VERSION 5.7 ;
BUSBITCHARS "[]" ;
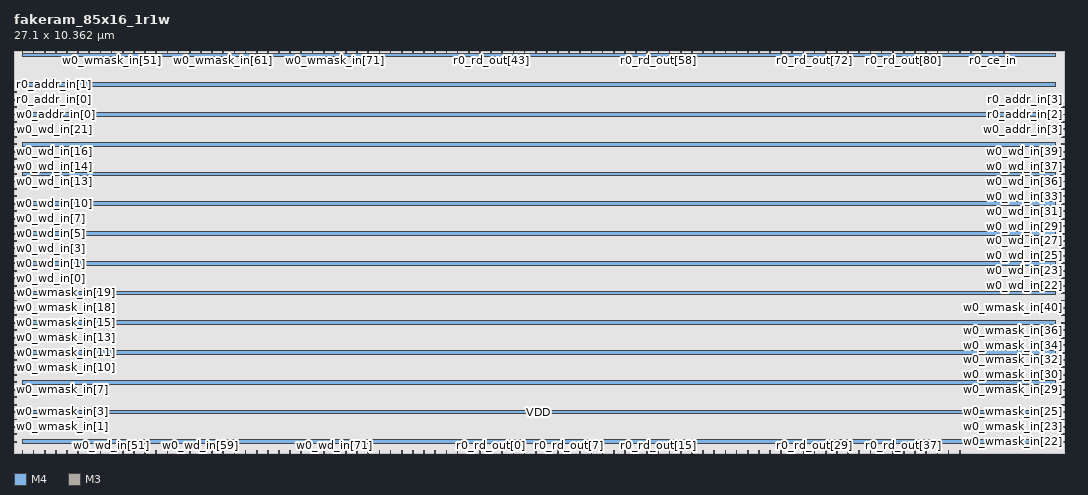
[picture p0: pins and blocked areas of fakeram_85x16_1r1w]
MACRO fakeram_85x16_1r1w
  FOREIGN fakeram_85x16_1r1w 0 0 ;
  SYMMETRY X Y R90 ;
  SIZE 27.100 BY 10.362 ;
  CLASS BLOCK ;
  PIN w0_wmask_in[0]
    DIRECTION INPUT ;
    USE SIGNAL ;
    SHAPE ABUTMENT ;
    PORT
      LAYER M4 ;
      RECT 0.000 0.276 0.072 0.300 ;
    END
  END w0_wmask_in[0]
  PIN w0_wmask_in[1]
    DIRECTION INPUT ;
    USE SIGNAL ;
    SHAPE ABUTMENT ;
    PORT
      LAYER M4 ;
      RECT 0.000 0.468 0.072 0.492 ;
    END
  END w0_wmask_in[1]
  PIN w0_wmask_in[2]
    DIRECTION INPUT ;
    USE SIGNAL ;
    SHAPE ABUTMENT ;
    PORT
      LAYER M4 ;
      RECT 0.000 0.660 0.072 0.684 ;
    END
  END w0_wmask_in[2]
  PIN w0_wmask_in[3]
    DIRECTION INPUT ;
    USE SIGNAL ;
    SHAPE ABUTMENT ;
    PORT
      LAYER M4 ;
      RECT 0.000 0.852 0.072 0.876 ;
    END
  END w0_wmask_in[3]
  PIN w0_wmask_in[4]
    DIRECTION INPUT ;
    USE SIGNAL ;
    SHAPE ABUTMENT ;
    PORT
      LAYER M4 ;
      RECT 0.000 1.044 0.072 1.068 ;
    END
  END w0_wmask_in[4]
  PIN w0_wmask_in[5]
    DIRECTION INPUT ;
    USE SIGNAL ;
    SHAPE ABUTMENT ;
    PORT
      LAYER M4 ;
      RECT 0.000 1.236 0.072 1.260 ;
    END
  END w0_wmask_in[5]
  PIN w0_wmask_in[6]
    DIRECTION INPUT ;
    USE SIGNAL ;
    SHAPE ABUTMENT ;
    PORT
      LAYER M4 ;
      RECT 0.000 1.428 0.072 1.452 ;
    END
  END w0_wmask_in[6]
  PIN w0_wmask_in[7]
    DIRECTION INPUT ;
    USE SIGNAL ;
    SHAPE ABUTMENT ;
    PORT
      LAYER M4 ;
      RECT 0.000 1.620 0.072 1.644 ;
    END
  END w0_wmask_in[7]
  PIN w0_wmask_in[8]
    DIRECTION INPUT ;
    USE SIGNAL ;
    SHAPE ABUTMENT ;
    PORT
      LAYER M4 ;
      RECT 0.000 1.812 0.072 1.836 ;
    END
  END w0_wmask_in[8]
  PIN w0_wmask_in[9]
    DIRECTION INPUT ;
    USE SIGNAL ;
    SHAPE ABUTMENT ;
    PORT
      LAYER M4 ;
      RECT 0.000 2.004 0.072 2.028 ;
    END
  END w0_wmask_in[9]
  PIN w0_wmask_in[10]
    DIRECTION INPUT ;
    USE SIGNAL ;
    SHAPE ABUTMENT ;
    PORT
      LAYER M4 ;
      RECT 0.000 2.196 0.072 2.220 ;
    END
  END w0_wmask_in[10]
  PIN w0_wmask_in[11]
    DIRECTION INPUT ;
    USE SIGNAL ;
    SHAPE ABUTMENT ;
    PORT
      LAYER M4 ;
      RECT 0.000 2.388 0.072 2.412 ;
    END
  END w0_wmask_in[11]
  PIN w0_wmask_in[12]
    DIRECTION INPUT ;
    USE SIGNAL ;
    SHAPE ABUTMENT ;
    PORT
      LAYER M4 ;
      RECT 0.000 2.580 0.072 2.604 ;
    END
  END w0_wmask_in[12]
  PIN w0_wmask_in[13]
    DIRECTION INPUT ;
    USE SIGNAL ;
    SHAPE ABUTMENT ;
    PORT
      LAYER M4 ;
      RECT 0.000 2.772 0.072 2.796 ;
    END
  END w0_wmask_in[13]
  PIN w0_wmask_in[14]
    DIRECTION INPUT ;
    USE SIGNAL ;
    SHAPE ABUTMENT ;
    PORT
      LAYER M4 ;
      RECT 0.000 2.964 0.072 2.988 ;
    END
  END w0_wmask_in[14]
  PIN w0_wmask_in[15]
    DIRECTION INPUT ;
    USE SIGNAL ;
    SHAPE ABUTMENT ;
    PORT
      LAYER M4 ;
      RECT 0.000 3.156 0.072 3.180 ;
    END
  END w0_wmask_in[15]
  PIN w0_wmask_in[16]
    DIRECTION INPUT ;
    USE SIGNAL ;
    SHAPE ABUTMENT ;
    PORT
      LAYER M4 ;
      RECT 0.000 3.348 0.072 3.372 ;
    END
  END w0_wmask_in[16]
  PIN w0_wmask_in[17]
    DIRECTION INPUT ;
    USE SIGNAL ;
    SHAPE ABUTMENT ;
    PORT
      LAYER M4 ;
      RECT 0.000 3.540 0.072 3.564 ;
    END
  END w0_wmask_in[17]
  PIN w0_wmask_in[18]
    DIRECTION INPUT ;
    USE SIGNAL ;
    SHAPE ABUTMENT ;
    PORT
      LAYER M4 ;
      RECT 0.000 3.732 0.072 3.756 ;
    END
  END w0_wmask_in[18]
  PIN w0_wmask_in[19]
    DIRECTION INPUT ;
    USE SIGNAL ;
    SHAPE ABUTMENT ;
    PORT
      LAYER M4 ;
      RECT 0.000 3.924 0.072 3.948 ;
    END
  END w0_wmask_in[19]
  PIN w0_wmask_in[20]
    DIRECTION INPUT ;
    USE SIGNAL ;
    SHAPE ABUTMENT ;
    PORT
      LAYER M4 ;
      RECT 0.000 4.116 0.072 4.140 ;
    END
  END w0_wmask_in[20]
  PIN w0_wmask_in[21]
    DIRECTION INPUT ;
    USE SIGNAL ;
    SHAPE ABUTMENT ;
    PORT
      LAYER M4 ;
      RECT 0.000 4.308 0.072 4.332 ;
    END
  END w0_wmask_in[21]
  PIN w0_wmask_in[22]
    DIRECTION INPUT ;
    USE SIGNAL ;
    SHAPE ABUTMENT ;
    PORT
      LAYER M4 ;
      RECT 27.028 0.276 27.100 0.300 ;
    END
  END w0_wmask_in[22]
  PIN w0_wmask_in[23]
    DIRECTION INPUT ;
    USE SIGNAL ;
    SHAPE ABUTMENT ;
    PORT
      LAYER M4 ;
      RECT 27.028 0.468 27.100 0.492 ;
    END
  END w0_wmask_in[23]
  PIN w0_wmask_in[24]
    DIRECTION INPUT ;
    USE SIGNAL ;
    SHAPE ABUTMENT ;
    PORT
      LAYER M4 ;
      RECT 27.028 0.660 27.100 0.684 ;
    END
  END w0_wmask_in[24]
  PIN w0_wmask_in[25]
    DIRECTION INPUT ;
    USE SIGNAL ;
    SHAPE ABUTMENT ;
    PORT
      LAYER M4 ;
      RECT 27.028 0.852 27.100 0.876 ;
    END
  END w0_wmask_in[25]
  PIN w0_wmask_in[26]
    DIRECTION INPUT ;
    USE SIGNAL ;
    SHAPE ABUTMENT ;
    PORT
      LAYER M4 ;
      RECT 27.028 1.044 27.100 1.068 ;
    END
  END w0_wmask_in[26]
  PIN w0_wmask_in[27]
    DIRECTION INPUT ;
    USE SIGNAL ;
    SHAPE ABUTMENT ;
    PORT
      LAYER M4 ;
      RECT 27.028 1.236 27.100 1.260 ;
    END
  END w0_wmask_in[27]
  PIN w0_wmask_in[28]
    DIRECTION INPUT ;
    USE SIGNAL ;
    SHAPE ABUTMENT ;
    PORT
      LAYER M4 ;
      RECT 27.028 1.428 27.100 1.452 ;
    END
  END w0_wmask_in[28]
  PIN w0_wmask_in[29]
    DIRECTION INPUT ;
    USE SIGNAL ;
    SHAPE ABUTMENT ;
    PORT
      LAYER M4 ;
      RECT 27.028 1.620 27.100 1.644 ;
    END
  END w0_wmask_in[29]
  PIN w0_wmask_in[30]
    DIRECTION INPUT ;
    USE SIGNAL ;
    SHAPE ABUTMENT ;
    PORT
      LAYER M4 ;
      RECT 27.028 1.812 27.100 1.836 ;
    END
  END w0_wmask_in[30]
  PIN w0_wmask_in[31]
    DIRECTION INPUT ;
    USE SIGNAL ;
    SHAPE ABUTMENT ;
    PORT
      LAYER M4 ;
      RECT 27.028 2.004 27.100 2.028 ;
    END
  END w0_wmask_in[31]
  PIN w0_wmask_in[32]
    DIRECTION INPUT ;
    USE SIGNAL ;
    SHAPE ABUTMENT ;
    PORT
      LAYER M4 ;
      RECT 27.028 2.196 27.100 2.220 ;
    END
  END w0_wmask_in[32]
  PIN w0_wmask_in[33]
    DIRECTION INPUT ;
    USE SIGNAL ;
    SHAPE ABUTMENT ;
    PORT
      LAYER M4 ;
      RECT 27.028 2.388 27.100 2.412 ;
    END
  END w0_wmask_in[33]
  PIN w0_wmask_in[34]
    DIRECTION INPUT ;
    USE SIGNAL ;
    SHAPE ABUTMENT ;
    PORT
      LAYER M4 ;
      RECT 27.028 2.580 27.100 2.604 ;
    END
  END w0_wmask_in[34]
  PIN w0_wmask_in[35]
    DIRECTION INPUT ;
    USE SIGNAL ;
    SHAPE ABUTMENT ;
    PORT
      LAYER M4 ;
      RECT 27.028 2.772 27.100 2.796 ;
    END
  END w0_wmask_in[35]
  PIN w0_wmask_in[36]
    DIRECTION INPUT ;
    USE SIGNAL ;
    SHAPE ABUTMENT ;
    PORT
      LAYER M4 ;
      RECT 27.028 2.964 27.100 2.988 ;
    END
  END w0_wmask_in[36]
  PIN w0_wmask_in[37]
    DIRECTION INPUT ;
    USE SIGNAL ;
    SHAPE ABUTMENT ;
    PORT
      LAYER M4 ;
      RECT 27.028 3.156 27.100 3.180 ;
    END
  END w0_wmask_in[37]
  PIN w0_wmask_in[38]
    DIRECTION INPUT ;
    USE SIGNAL ;
    SHAPE ABUTMENT ;
    PORT
      LAYER M4 ;
      RECT 27.028 3.348 27.100 3.372 ;
    END
  END w0_wmask_in[38]
  PIN w0_wmask_in[39]
    DIRECTION INPUT ;
    USE SIGNAL ;
    SHAPE ABUTMENT ;
    PORT
      LAYER M4 ;
      RECT 27.028 3.540 27.100 3.564 ;
    END
  END w0_wmask_in[39]
  PIN w0_wmask_in[40]
    DIRECTION INPUT ;
    USE SIGNAL ;
    SHAPE ABUTMENT ;
    PORT
      LAYER M4 ;
      RECT 27.028 3.732 27.100 3.756 ;
    END
  END w0_wmask_in[40]
  PIN w0_wmask_in[41]
    DIRECTION INPUT ;
    USE SIGNAL ;
    SHAPE ABUTMENT ;
    PORT
      LAYER M4 ;
      RECT 27.028 3.924 27.100 3.948 ;
    END
  END w0_wmask_in[41]
  PIN w0_wmask_in[42]
    DIRECTION INPUT ;
    USE SIGNAL ;
    SHAPE ABUTMENT ;
    PORT
      LAYER M4 ;
      RECT 27.028 4.116 27.100 4.140 ;
    END
  END w0_wmask_in[42]
  PIN w0_wmask_in[43]
    DIRECTION INPUT ;
    USE SIGNAL ;
    SHAPE ABUTMENT ;
    PORT
      LAYER M3 ;
      RECT 0.207 10.308 0.225 10.362 ;
    END
  END w0_wmask_in[43]
  PIN w0_wmask_in[44]
    DIRECTION INPUT ;
    USE SIGNAL ;
    SHAPE ABUTMENT ;
    PORT
      LAYER M3 ;
      RECT 0.495 10.308 0.513 10.362 ;
    END
  END w0_wmask_in[44]
  PIN w0_wmask_in[45]
    DIRECTION INPUT ;
    USE SIGNAL ;
    SHAPE ABUTMENT ;
    PORT
      LAYER M3 ;
      RECT 0.783 10.308 0.801 10.362 ;
    END
  END w0_wmask_in[45]
  PIN w0_wmask_in[46]
    DIRECTION INPUT ;
    USE SIGNAL ;
    SHAPE ABUTMENT ;
    PORT
      LAYER M3 ;
      RECT 1.071 10.308 1.089 10.362 ;
    END
  END w0_wmask_in[46]
  PIN w0_wmask_in[47]
    DIRECTION INPUT ;
    USE SIGNAL ;
    SHAPE ABUTMENT ;
    PORT
      LAYER M3 ;
      RECT 1.359 10.308 1.377 10.362 ;
    END
  END w0_wmask_in[47]
  PIN w0_wmask_in[48]
    DIRECTION INPUT ;
    USE SIGNAL ;
    SHAPE ABUTMENT ;
    PORT
      LAYER M3 ;
      RECT 1.647 10.308 1.665 10.362 ;
    END
  END w0_wmask_in[48]
  PIN w0_wmask_in[49]
    DIRECTION INPUT ;
    USE SIGNAL ;
    SHAPE ABUTMENT ;
    PORT
      LAYER M3 ;
      RECT 1.935 10.308 1.953 10.362 ;
    END
  END w0_wmask_in[49]
  PIN w0_wmask_in[50]
    DIRECTION INPUT ;
    USE SIGNAL ;
    SHAPE ABUTMENT ;
    PORT
      LAYER M3 ;
      RECT 2.223 10.308 2.241 10.362 ;
    END
  END w0_wmask_in[50]
  PIN w0_wmask_in[51]
    DIRECTION INPUT ;
    USE SIGNAL ;
    SHAPE ABUTMENT ;
    PORT
      LAYER M3 ;
      RECT 2.511 10.308 2.529 10.362 ;
    END
  END w0_wmask_in[51]
  PIN w0_wmask_in[52]
    DIRECTION INPUT ;
    USE SIGNAL ;
    SHAPE ABUTMENT ;
    PORT
      LAYER M3 ;
      RECT 2.799 10.308 2.817 10.362 ;
    END
  END w0_wmask_in[52]
  PIN w0_wmask_in[53]
    DIRECTION INPUT ;
    USE SIGNAL ;
    SHAPE ABUTMENT ;
    PORT
      LAYER M3 ;
      RECT 3.087 10.308 3.105 10.362 ;
    END
  END w0_wmask_in[53]
  PIN w0_wmask_in[54]
    DIRECTION INPUT ;
    USE SIGNAL ;
    SHAPE ABUTMENT ;
    PORT
      LAYER M3 ;
      RECT 3.375 10.308 3.393 10.362 ;
    END
  END w0_wmask_in[54]
  PIN w0_wmask_in[55]
    DIRECTION INPUT ;
    USE SIGNAL ;
    SHAPE ABUTMENT ;
    PORT
      LAYER M3 ;
      RECT 3.663 10.308 3.681 10.362 ;
    END
  END w0_wmask_in[55]
  PIN w0_wmask_in[56]
    DIRECTION INPUT ;
    USE SIGNAL ;
    SHAPE ABUTMENT ;
    PORT
      LAYER M3 ;
      RECT 3.951 10.308 3.969 10.362 ;
    END
  END w0_wmask_in[56]
  PIN w0_wmask_in[57]
    DIRECTION INPUT ;
    USE SIGNAL ;
    SHAPE ABUTMENT ;
    PORT
      LAYER M3 ;
      RECT 4.239 10.308 4.257 10.362 ;
    END
  END w0_wmask_in[57]
  PIN w0_wmask_in[58]
    DIRECTION INPUT ;
    USE SIGNAL ;
    SHAPE ABUTMENT ;
    PORT
      LAYER M3 ;
      RECT 4.527 10.308 4.545 10.362 ;
    END
  END w0_wmask_in[58]
  PIN w0_wmask_in[59]
    DIRECTION INPUT ;
    USE SIGNAL ;
    SHAPE ABUTMENT ;
    PORT
      LAYER M3 ;
      RECT 4.815 10.308 4.833 10.362 ;
    END
  END w0_wmask_in[59]
  PIN w0_wmask_in[60]
    DIRECTION INPUT ;
    USE SIGNAL ;
    SHAPE ABUTMENT ;
    PORT
      LAYER M3 ;
      RECT 5.103 10.308 5.121 10.362 ;
    END
  END w0_wmask_in[60]
  PIN w0_wmask_in[61]
    DIRECTION INPUT ;
    USE SIGNAL ;
    SHAPE ABUTMENT ;
    PORT
      LAYER M3 ;
      RECT 5.391 10.308 5.409 10.362 ;
    END
  END w0_wmask_in[61]
  PIN w0_wmask_in[62]
    DIRECTION INPUT ;
    USE SIGNAL ;
    SHAPE ABUTMENT ;
    PORT
      LAYER M3 ;
      RECT 5.679 10.308 5.697 10.362 ;
    END
  END w0_wmask_in[62]
  PIN w0_wmask_in[63]
    DIRECTION INPUT ;
    USE SIGNAL ;
    SHAPE ABUTMENT ;
    PORT
      LAYER M3 ;
      RECT 5.967 10.308 5.985 10.362 ;
    END
  END w0_wmask_in[63]
  PIN w0_wmask_in[64]
    DIRECTION INPUT ;
    USE SIGNAL ;
    SHAPE ABUTMENT ;
    PORT
      LAYER M3 ;
      RECT 6.255 10.308 6.273 10.362 ;
    END
  END w0_wmask_in[64]
  PIN w0_wmask_in[65]
    DIRECTION INPUT ;
    USE SIGNAL ;
    SHAPE ABUTMENT ;
    PORT
      LAYER M3 ;
      RECT 6.543 10.308 6.561 10.362 ;
    END
  END w0_wmask_in[65]
  PIN w0_wmask_in[66]
    DIRECTION INPUT ;
    USE SIGNAL ;
    SHAPE ABUTMENT ;
    PORT
      LAYER M3 ;
      RECT 6.831 10.308 6.849 10.362 ;
    END
  END w0_wmask_in[66]
  PIN w0_wmask_in[67]
    DIRECTION INPUT ;
    USE SIGNAL ;
    SHAPE ABUTMENT ;
    PORT
      LAYER M3 ;
      RECT 7.119 10.308 7.137 10.362 ;
    END
  END w0_wmask_in[67]
  PIN w0_wmask_in[68]
    DIRECTION INPUT ;
    USE SIGNAL ;
    SHAPE ABUTMENT ;
    PORT
      LAYER M3 ;
      RECT 7.407 10.308 7.425 10.362 ;
    END
  END w0_wmask_in[68]
  PIN w0_wmask_in[69]
    DIRECTION INPUT ;
    USE SIGNAL ;
    SHAPE ABUTMENT ;
    PORT
      LAYER M3 ;
      RECT 7.695 10.308 7.713 10.362 ;
    END
  END w0_wmask_in[69]
  PIN w0_wmask_in[70]
    DIRECTION INPUT ;
    USE SIGNAL ;
    SHAPE ABUTMENT ;
    PORT
      LAYER M3 ;
      RECT 7.983 10.308 8.001 10.362 ;
    END
  END w0_wmask_in[70]
  PIN w0_wmask_in[71]
    DIRECTION INPUT ;
    USE SIGNAL ;
    SHAPE ABUTMENT ;
    PORT
      LAYER M3 ;
      RECT 8.271 10.308 8.289 10.362 ;
    END
  END w0_wmask_in[71]
  PIN w0_wmask_in[72]
    DIRECTION INPUT ;
    USE SIGNAL ;
    SHAPE ABUTMENT ;
    PORT
      LAYER M3 ;
      RECT 8.559 10.308 8.577 10.362 ;
    END
  END w0_wmask_in[72]
  PIN w0_wmask_in[73]
    DIRECTION INPUT ;
    USE SIGNAL ;
    SHAPE ABUTMENT ;
    PORT
      LAYER M3 ;
      RECT 8.847 10.308 8.865 10.362 ;
    END
  END w0_wmask_in[73]
  PIN w0_wmask_in[74]
    DIRECTION INPUT ;
    USE SIGNAL ;
    SHAPE ABUTMENT ;
    PORT
      LAYER M3 ;
      RECT 9.135 10.308 9.153 10.362 ;
    END
  END w0_wmask_in[74]
  PIN w0_wmask_in[75]
    DIRECTION INPUT ;
    USE SIGNAL ;
    SHAPE ABUTMENT ;
    PORT
      LAYER M3 ;
      RECT 9.423 10.308 9.441 10.362 ;
    END
  END w0_wmask_in[75]
  PIN w0_wmask_in[76]
    DIRECTION INPUT ;
    USE SIGNAL ;
    SHAPE ABUTMENT ;
    PORT
      LAYER M3 ;
      RECT 9.711 10.308 9.729 10.362 ;
    END
  END w0_wmask_in[76]
  PIN w0_wmask_in[77]
    DIRECTION INPUT ;
    USE SIGNAL ;
    SHAPE ABUTMENT ;
    PORT
      LAYER M3 ;
      RECT 9.999 10.308 10.017 10.362 ;
    END
  END w0_wmask_in[77]
  PIN w0_wmask_in[78]
    DIRECTION INPUT ;
    USE SIGNAL ;
    SHAPE ABUTMENT ;
    PORT
      LAYER M3 ;
      RECT 10.287 10.308 10.305 10.362 ;
    END
  END w0_wmask_in[78]
  PIN w0_wmask_in[79]
    DIRECTION INPUT ;
    USE SIGNAL ;
    SHAPE ABUTMENT ;
    PORT
      LAYER M3 ;
      RECT 10.575 10.308 10.593 10.362 ;
    END
  END w0_wmask_in[79]
  PIN w0_wmask_in[80]
    DIRECTION INPUT ;
    USE SIGNAL ;
    SHAPE ABUTMENT ;
    PORT
      LAYER M3 ;
      RECT 10.863 10.308 10.881 10.362 ;
    END
  END w0_wmask_in[80]
  PIN w0_wmask_in[81]
    DIRECTION INPUT ;
    USE SIGNAL ;
    SHAPE ABUTMENT ;
    PORT
      LAYER M3 ;
      RECT 11.151 10.308 11.169 10.362 ;
    END
  END w0_wmask_in[81]
  PIN w0_wmask_in[82]
    DIRECTION INPUT ;
    USE SIGNAL ;
    SHAPE ABUTMENT ;
    PORT
      LAYER M3 ;
      RECT 11.439 10.308 11.457 10.362 ;
    END
  END w0_wmask_in[82]
  PIN w0_wmask_in[83]
    DIRECTION INPUT ;
    USE SIGNAL ;
    SHAPE ABUTMENT ;
    PORT
      LAYER M3 ;
      RECT 11.727 10.308 11.745 10.362 ;
    END
  END w0_wmask_in[83]
  PIN w0_wmask_in[84]
    DIRECTION INPUT ;
    USE SIGNAL ;
    SHAPE ABUTMENT ;
    PORT
      LAYER M3 ;
      RECT 12.015 10.308 12.033 10.362 ;
    END
  END w0_wmask_in[84]
  PIN w0_wd_in[0]
    DIRECTION INPUT ;
    USE SIGNAL ;
    SHAPE ABUTMENT ;
    PORT
      LAYER M4 ;
      RECT 0.000 4.500 0.072 4.524 ;
    END
  END w0_wd_in[0]
  PIN w0_wd_in[1]
    DIRECTION INPUT ;
    USE SIGNAL ;
    SHAPE ABUTMENT ;
    PORT
      LAYER M4 ;
      RECT 0.000 4.692 0.072 4.716 ;
    END
  END w0_wd_in[1]
  PIN w0_wd_in[2]
    DIRECTION INPUT ;
    USE SIGNAL ;
    SHAPE ABUTMENT ;
    PORT
      LAYER M4 ;
      RECT 0.000 4.884 0.072 4.908 ;
    END
  END w0_wd_in[2]
  PIN w0_wd_in[3]
    DIRECTION INPUT ;
    USE SIGNAL ;
    SHAPE ABUTMENT ;
    PORT
      LAYER M4 ;
      RECT 0.000 5.076 0.072 5.100 ;
    END
  END w0_wd_in[3]
  PIN w0_wd_in[4]
    DIRECTION INPUT ;
    USE SIGNAL ;
    SHAPE ABUTMENT ;
    PORT
      LAYER M4 ;
      RECT 0.000 5.268 0.072 5.292 ;
    END
  END w0_wd_in[4]
  PIN w0_wd_in[5]
    DIRECTION INPUT ;
    USE SIGNAL ;
    SHAPE ABUTMENT ;
    PORT
      LAYER M4 ;
      RECT 0.000 5.460 0.072 5.484 ;
    END
  END w0_wd_in[5]
  PIN w0_wd_in[6]
    DIRECTION INPUT ;
    USE SIGNAL ;
    SHAPE ABUTMENT ;
    PORT
      LAYER M4 ;
      RECT 0.000 5.652 0.072 5.676 ;
    END
  END w0_wd_in[6]
  PIN w0_wd_in[7]
    DIRECTION INPUT ;
    USE SIGNAL ;
    SHAPE ABUTMENT ;
    PORT
      LAYER M4 ;
      RECT 0.000 5.844 0.072 5.868 ;
    END
  END w0_wd_in[7]
  PIN w0_wd_in[8]
    DIRECTION INPUT ;
    USE SIGNAL ;
    SHAPE ABUTMENT ;
    PORT
      LAYER M4 ;
      RECT 0.000 6.036 0.072 6.060 ;
    END
  END w0_wd_in[8]
  PIN w0_wd_in[9]
    DIRECTION INPUT ;
    USE SIGNAL ;
    SHAPE ABUTMENT ;
    PORT
      LAYER M4 ;
      RECT 0.000 6.228 0.072 6.252 ;
    END
  END w0_wd_in[9]
  PIN w0_wd_in[10]
    DIRECTION INPUT ;
    USE SIGNAL ;
    SHAPE ABUTMENT ;
    PORT
      LAYER M4 ;
      RECT 0.000 6.420 0.072 6.444 ;
    END
  END w0_wd_in[10]
  PIN w0_wd_in[11]
    DIRECTION INPUT ;
    USE SIGNAL ;
    SHAPE ABUTMENT ;
    PORT
      LAYER M4 ;
      RECT 0.000 6.612 0.072 6.636 ;
    END
  END w0_wd_in[11]
  PIN w0_wd_in[12]
    DIRECTION INPUT ;
    USE SIGNAL ;
    SHAPE ABUTMENT ;
    PORT
      LAYER M4 ;
      RECT 0.000 6.804 0.072 6.828 ;
    END
  END w0_wd_in[12]
  PIN w0_wd_in[13]
    DIRECTION INPUT ;
    USE SIGNAL ;
    SHAPE ABUTMENT ;
    PORT
      LAYER M4 ;
      RECT 0.000 6.996 0.072 7.020 ;
    END
  END w0_wd_in[13]
  PIN w0_wd_in[14]
    DIRECTION INPUT ;
    USE SIGNAL ;
    SHAPE ABUTMENT ;
    PORT
      LAYER M4 ;
      RECT 0.000 7.188 0.072 7.212 ;
    END
  END w0_wd_in[14]
  PIN w0_wd_in[15]
    DIRECTION INPUT ;
    USE SIGNAL ;
    SHAPE ABUTMENT ;
    PORT
      LAYER M4 ;
      RECT 0.000 7.380 0.072 7.404 ;
    END
  END w0_wd_in[15]
  PIN w0_wd_in[16]
    DIRECTION INPUT ;
    USE SIGNAL ;
    SHAPE ABUTMENT ;
    PORT
      LAYER M4 ;
      RECT 0.000 7.572 0.072 7.596 ;
    END
  END w0_wd_in[16]
  PIN w0_wd_in[17]
    DIRECTION INPUT ;
    USE SIGNAL ;
    SHAPE ABUTMENT ;
    PORT
      LAYER M4 ;
      RECT 0.000 7.764 0.072 7.788 ;
    END
  END w0_wd_in[17]
  PIN w0_wd_in[18]
    DIRECTION INPUT ;
    USE SIGNAL ;
    SHAPE ABUTMENT ;
    PORT
      LAYER M4 ;
      RECT 0.000 7.956 0.072 7.980 ;
    END
  END w0_wd_in[18]
  PIN w0_wd_in[19]
    DIRECTION INPUT ;
    USE SIGNAL ;
    SHAPE ABUTMENT ;
    PORT
      LAYER M4 ;
      RECT 0.000 8.148 0.072 8.172 ;
    END
  END w0_wd_in[19]
  PIN w0_wd_in[20]
    DIRECTION INPUT ;
    USE SIGNAL ;
    SHAPE ABUTMENT ;
    PORT
      LAYER M4 ;
      RECT 0.000 8.340 0.072 8.364 ;
    END
  END w0_wd_in[20]
  PIN w0_wd_in[21]
    DIRECTION INPUT ;
    USE SIGNAL ;
    SHAPE ABUTMENT ;
    PORT
      LAYER M4 ;
      RECT 0.000 8.532 0.072 8.556 ;
    END
  END w0_wd_in[21]
  PIN w0_wd_in[22]
    DIRECTION INPUT ;
    USE SIGNAL ;
    SHAPE ABUTMENT ;
    PORT
      LAYER M4 ;
      RECT 27.028 4.308 27.100 4.332 ;
    END
  END w0_wd_in[22]
  PIN w0_wd_in[23]
    DIRECTION INPUT ;
    USE SIGNAL ;
    SHAPE ABUTMENT ;
    PORT
      LAYER M4 ;
      RECT 27.028 4.500 27.100 4.524 ;
    END
  END w0_wd_in[23]
  PIN w0_wd_in[24]
    DIRECTION INPUT ;
    USE SIGNAL ;
    SHAPE ABUTMENT ;
    PORT
      LAYER M4 ;
      RECT 27.028 4.692 27.100 4.716 ;
    END
  END w0_wd_in[24]
  PIN w0_wd_in[25]
    DIRECTION INPUT ;
    USE SIGNAL ;
    SHAPE ABUTMENT ;
    PORT
      LAYER M4 ;
      RECT 27.028 4.884 27.100 4.908 ;
    END
  END w0_wd_in[25]
  PIN w0_wd_in[26]
    DIRECTION INPUT ;
    USE SIGNAL ;
    SHAPE ABUTMENT ;
    PORT
      LAYER M4 ;
      RECT 27.028 5.076 27.100 5.100 ;
    END
  END w0_wd_in[26]
  PIN w0_wd_in[27]
    DIRECTION INPUT ;
    USE SIGNAL ;
    SHAPE ABUTMENT ;
    PORT
      LAYER M4 ;
      RECT 27.028 5.268 27.100 5.292 ;
    END
  END w0_wd_in[27]
  PIN w0_wd_in[28]
    DIRECTION INPUT ;
    USE SIGNAL ;
    SHAPE ABUTMENT ;
    PORT
      LAYER M4 ;
      RECT 27.028 5.460 27.100 5.484 ;
    END
  END w0_wd_in[28]
  PIN w0_wd_in[29]
    DIRECTION INPUT ;
    USE SIGNAL ;
    SHAPE ABUTMENT ;
    PORT
      LAYER M4 ;
      RECT 27.028 5.652 27.100 5.676 ;
    END
  END w0_wd_in[29]
  PIN w0_wd_in[30]
    DIRECTION INPUT ;
    USE SIGNAL ;
    SHAPE ABUTMENT ;
    PORT
      LAYER M4 ;
      RECT 27.028 5.844 27.100 5.868 ;
    END
  END w0_wd_in[30]
  PIN w0_wd_in[31]
    DIRECTION INPUT ;
    USE SIGNAL ;
    SHAPE ABUTMENT ;
    PORT
      LAYER M4 ;
      RECT 27.028 6.036 27.100 6.060 ;
    END
  END w0_wd_in[31]
  PIN w0_wd_in[32]
    DIRECTION INPUT ;
    USE SIGNAL ;
    SHAPE ABUTMENT ;
    PORT
      LAYER M4 ;
      RECT 27.028 6.228 27.100 6.252 ;
    END
  END w0_wd_in[32]
  PIN w0_wd_in[33]
    DIRECTION INPUT ;
    USE SIGNAL ;
    SHAPE ABUTMENT ;
    PORT
      LAYER M4 ;
      RECT 27.028 6.420 27.100 6.444 ;
    END
  END w0_wd_in[33]
  PIN w0_wd_in[34]
    DIRECTION INPUT ;
    USE SIGNAL ;
    SHAPE ABUTMENT ;
    PORT
      LAYER M4 ;
      RECT 27.028 6.612 27.100 6.636 ;
    END
  END w0_wd_in[34]
  PIN w0_wd_in[35]
    DIRECTION INPUT ;
    USE SIGNAL ;
    SHAPE ABUTMENT ;
    PORT
      LAYER M4 ;
      RECT 27.028 6.804 27.100 6.828 ;
    END
  END w0_wd_in[35]
  PIN w0_wd_in[36]
    DIRECTION INPUT ;
    USE SIGNAL ;
    SHAPE ABUTMENT ;
    PORT
      LAYER M4 ;
      RECT 27.028 6.996 27.100 7.020 ;
    END
  END w0_wd_in[36]
  PIN w0_wd_in[37]
    DIRECTION INPUT ;
    USE SIGNAL ;
    SHAPE ABUTMENT ;
    PORT
      LAYER M4 ;
      RECT 27.028 7.188 27.100 7.212 ;
    END
  END w0_wd_in[37]
  PIN w0_wd_in[38]
    DIRECTION INPUT ;
    USE SIGNAL ;
    SHAPE ABUTMENT ;
    PORT
      LAYER M4 ;
      RECT 27.028 7.380 27.100 7.404 ;
    END
  END w0_wd_in[38]
  PIN w0_wd_in[39]
    DIRECTION INPUT ;
    USE SIGNAL ;
    SHAPE ABUTMENT ;
    PORT
      LAYER M4 ;
      RECT 27.028 7.572 27.100 7.596 ;
    END
  END w0_wd_in[39]
  PIN w0_wd_in[40]
    DIRECTION INPUT ;
    USE SIGNAL ;
    SHAPE ABUTMENT ;
    PORT
      LAYER M4 ;
      RECT 27.028 7.764 27.100 7.788 ;
    END
  END w0_wd_in[40]
  PIN w0_wd_in[41]
    DIRECTION INPUT ;
    USE SIGNAL ;
    SHAPE ABUTMENT ;
    PORT
      LAYER M4 ;
      RECT 27.028 7.956 27.100 7.980 ;
    END
  END w0_wd_in[41]
  PIN w0_wd_in[42]
    DIRECTION INPUT ;
    USE SIGNAL ;
    SHAPE ABUTMENT ;
    PORT
      LAYER M4 ;
      RECT 27.028 8.148 27.100 8.172 ;
    END
  END w0_wd_in[42]
  PIN w0_wd_in[43]
    DIRECTION OUTPUT ;
    USE SIGNAL ;
    SHAPE ABUTMENT ;
    PORT
      LAYER M3 ;
      RECT 0.207 0.000 0.225 0.054 ;
    END
  END w0_wd_in[43]
  PIN w0_wd_in[44]
    DIRECTION OUTPUT ;
    USE SIGNAL ;
    SHAPE ABUTMENT ;
    PORT
      LAYER M3 ;
      RECT 0.495 0.000 0.513 0.054 ;
    END
  END w0_wd_in[44]
  PIN w0_wd_in[45]
    DIRECTION OUTPUT ;
    USE SIGNAL ;
    SHAPE ABUTMENT ;
    PORT
      LAYER M3 ;
      RECT 0.783 0.000 0.801 0.054 ;
    END
  END w0_wd_in[45]
  PIN w0_wd_in[46]
    DIRECTION OUTPUT ;
    USE SIGNAL ;
    SHAPE ABUTMENT ;
    PORT
      LAYER M3 ;
      RECT 1.071 0.000 1.089 0.054 ;
    END
  END w0_wd_in[46]
  PIN w0_wd_in[47]
    DIRECTION OUTPUT ;
    USE SIGNAL ;
    SHAPE ABUTMENT ;
    PORT
      LAYER M3 ;
      RECT 1.359 0.000 1.377 0.054 ;
    END
  END w0_wd_in[47]
  PIN w0_wd_in[48]
    DIRECTION OUTPUT ;
    USE SIGNAL ;
    SHAPE ABUTMENT ;
    PORT
      LAYER M3 ;
      RECT 1.647 0.000 1.665 0.054 ;
    END
  END w0_wd_in[48]
  PIN w0_wd_in[49]
    DIRECTION OUTPUT ;
    USE SIGNAL ;
    SHAPE ABUTMENT ;
    PORT
      LAYER M3 ;
      RECT 1.935 0.000 1.953 0.054 ;
    END
  END w0_wd_in[49]
  PIN w0_wd_in[50]
    DIRECTION OUTPUT ;
    USE SIGNAL ;
    SHAPE ABUTMENT ;
    PORT
      LAYER M3 ;
      RECT 2.223 0.000 2.241 0.054 ;
    END
  END w0_wd_in[50]
  PIN w0_wd_in[51]
    DIRECTION OUTPUT ;
    USE SIGNAL ;
    SHAPE ABUTMENT ;
    PORT
      LAYER M3 ;
      RECT 2.511 0.000 2.529 0.054 ;
    END
  END w0_wd_in[51]
  PIN w0_wd_in[52]
    DIRECTION OUTPUT ;
    USE SIGNAL ;
    SHAPE ABUTMENT ;
    PORT
      LAYER M3 ;
      RECT 2.799 0.000 2.817 0.054 ;
    END
  END w0_wd_in[52]
  PIN w0_wd_in[53]
    DIRECTION OUTPUT ;
    USE SIGNAL ;
    SHAPE ABUTMENT ;
    PORT
      LAYER M3 ;
      RECT 3.087 0.000 3.105 0.054 ;
    END
  END w0_wd_in[53]
  PIN w0_wd_in[54]
    DIRECTION OUTPUT ;
    USE SIGNAL ;
    SHAPE ABUTMENT ;
    PORT
      LAYER M3 ;
      RECT 3.375 0.000 3.393 0.054 ;
    END
  END w0_wd_in[54]
  PIN w0_wd_in[55]
    DIRECTION OUTPUT ;
    USE SIGNAL ;
    SHAPE ABUTMENT ;
    PORT
      LAYER M3 ;
      RECT 3.663 0.000 3.681 0.054 ;
    END
  END w0_wd_in[55]
  PIN w0_wd_in[56]
    DIRECTION OUTPUT ;
    USE SIGNAL ;
    SHAPE ABUTMENT ;
    PORT
      LAYER M3 ;
      RECT 3.951 0.000 3.969 0.054 ;
    END
  END w0_wd_in[56]
  PIN w0_wd_in[57]
    DIRECTION OUTPUT ;
    USE SIGNAL ;
    SHAPE ABUTMENT ;
    PORT
      LAYER M3 ;
      RECT 4.239 0.000 4.257 0.054 ;
    END
  END w0_wd_in[57]
  PIN w0_wd_in[58]
    DIRECTION OUTPUT ;
    USE SIGNAL ;
    SHAPE ABUTMENT ;
    PORT
      LAYER M3 ;
      RECT 4.527 0.000 4.545 0.054 ;
    END
  END w0_wd_in[58]
  PIN w0_wd_in[59]
    DIRECTION OUTPUT ;
    USE SIGNAL ;
    SHAPE ABUTMENT ;
    PORT
      LAYER M3 ;
      RECT 4.815 0.000 4.833 0.054 ;
    END
  END w0_wd_in[59]
  PIN w0_wd_in[60]
    DIRECTION OUTPUT ;
    USE SIGNAL ;
    SHAPE ABUTMENT ;
    PORT
      LAYER M3 ;
      RECT 5.103 0.000 5.121 0.054 ;
    END
  END w0_wd_in[60]
  PIN w0_wd_in[61]
    DIRECTION OUTPUT ;
    USE SIGNAL ;
    SHAPE ABUTMENT ;
    PORT
      LAYER M3 ;
      RECT 5.391 0.000 5.409 0.054 ;
    END
  END w0_wd_in[61]
  PIN w0_wd_in[62]
    DIRECTION OUTPUT ;
    USE SIGNAL ;
    SHAPE ABUTMENT ;
    PORT
      LAYER M3 ;
      RECT 5.679 0.000 5.697 0.054 ;
    END
  END w0_wd_in[62]
  PIN w0_wd_in[63]
    DIRECTION OUTPUT ;
    USE SIGNAL ;
    SHAPE ABUTMENT ;
    PORT
      LAYER M3 ;
      RECT 5.967 0.000 5.985 0.054 ;
    END
  END w0_wd_in[63]
  PIN w0_wd_in[64]
    DIRECTION OUTPUT ;
    USE SIGNAL ;
    SHAPE ABUTMENT ;
    PORT
      LAYER M3 ;
      RECT 6.255 0.000 6.273 0.054 ;
    END
  END w0_wd_in[64]
  PIN w0_wd_in[65]
    DIRECTION OUTPUT ;
    USE SIGNAL ;
    SHAPE ABUTMENT ;
    PORT
      LAYER M3 ;
      RECT 6.543 0.000 6.561 0.054 ;
    END
  END w0_wd_in[65]
  PIN w0_wd_in[66]
    DIRECTION OUTPUT ;
    USE SIGNAL ;
    SHAPE ABUTMENT ;
    PORT
      LAYER M3 ;
      RECT 6.831 0.000 6.849 0.054 ;
    END
  END w0_wd_in[66]
  PIN w0_wd_in[67]
    DIRECTION OUTPUT ;
    USE SIGNAL ;
    SHAPE ABUTMENT ;
    PORT
      LAYER M3 ;
      RECT 7.119 0.000 7.137 0.054 ;
    END
  END w0_wd_in[67]
  PIN w0_wd_in[68]
    DIRECTION OUTPUT ;
    USE SIGNAL ;
    SHAPE ABUTMENT ;
    PORT
      LAYER M3 ;
      RECT 7.407 0.000 7.425 0.054 ;
    END
  END w0_wd_in[68]
  PIN w0_wd_in[69]
    DIRECTION OUTPUT ;
    USE SIGNAL ;
    SHAPE ABUTMENT ;
    PORT
      LAYER M3 ;
      RECT 7.695 0.000 7.713 0.054 ;
    END
  END w0_wd_in[69]
  PIN w0_wd_in[70]
    DIRECTION OUTPUT ;
    USE SIGNAL ;
    SHAPE ABUTMENT ;
    PORT
      LAYER M3 ;
      RECT 7.983 0.000 8.001 0.054 ;
    END
  END w0_wd_in[70]
  PIN w0_wd_in[71]
    DIRECTION OUTPUT ;
    USE SIGNAL ;
    SHAPE ABUTMENT ;
    PORT
      LAYER M3 ;
      RECT 8.271 0.000 8.289 0.054 ;
    END
  END w0_wd_in[71]
  PIN w0_wd_in[72]
    DIRECTION OUTPUT ;
    USE SIGNAL ;
    SHAPE ABUTMENT ;
    PORT
      LAYER M3 ;
      RECT 8.559 0.000 8.577 0.054 ;
    END
  END w0_wd_in[72]
  PIN w0_wd_in[73]
    DIRECTION OUTPUT ;
    USE SIGNAL ;
    SHAPE ABUTMENT ;
    PORT
      LAYER M3 ;
      RECT 8.847 0.000 8.865 0.054 ;
    END
  END w0_wd_in[73]
  PIN w0_wd_in[74]
    DIRECTION OUTPUT ;
    USE SIGNAL ;
    SHAPE ABUTMENT ;
    PORT
      LAYER M3 ;
      RECT 9.135 0.000 9.153 0.054 ;
    END
  END w0_wd_in[74]
  PIN w0_wd_in[75]
    DIRECTION OUTPUT ;
    USE SIGNAL ;
    SHAPE ABUTMENT ;
    PORT
      LAYER M3 ;
      RECT 9.423 0.000 9.441 0.054 ;
    END
  END w0_wd_in[75]
  PIN w0_wd_in[76]
    DIRECTION OUTPUT ;
    USE SIGNAL ;
    SHAPE ABUTMENT ;
    PORT
      LAYER M3 ;
      RECT 9.711 0.000 9.729 0.054 ;
    END
  END w0_wd_in[76]
  PIN w0_wd_in[77]
    DIRECTION OUTPUT ;
    USE SIGNAL ;
    SHAPE ABUTMENT ;
    PORT
      LAYER M3 ;
      RECT 9.999 0.000 10.017 0.054 ;
    END
  END w0_wd_in[77]
  PIN w0_wd_in[78]
    DIRECTION OUTPUT ;
    USE SIGNAL ;
    SHAPE ABUTMENT ;
    PORT
      LAYER M3 ;
      RECT 10.287 0.000 10.305 0.054 ;
    END
  END w0_wd_in[78]
  PIN w0_wd_in[79]
    DIRECTION OUTPUT ;
    USE SIGNAL ;
    SHAPE ABUTMENT ;
    PORT
      LAYER M3 ;
      RECT 10.575 0.000 10.593 0.054 ;
    END
  END w0_wd_in[79]
  PIN w0_wd_in[80]
    DIRECTION OUTPUT ;
    USE SIGNAL ;
    SHAPE ABUTMENT ;
    PORT
      LAYER M3 ;
      RECT 10.863 0.000 10.881 0.054 ;
    END
  END w0_wd_in[80]
  PIN w0_wd_in[81]
    DIRECTION OUTPUT ;
    USE SIGNAL ;
    SHAPE ABUTMENT ;
    PORT
      LAYER M3 ;
      RECT 11.151 0.000 11.169 0.054 ;
    END
  END w0_wd_in[81]
  PIN w0_wd_in[82]
    DIRECTION OUTPUT ;
    USE SIGNAL ;
    SHAPE ABUTMENT ;
    PORT
      LAYER M3 ;
      RECT 11.439 0.000 11.457 0.054 ;
    END
  END w0_wd_in[82]
  PIN w0_wd_in[83]
    DIRECTION OUTPUT ;
    USE SIGNAL ;
    SHAPE ABUTMENT ;
    PORT
      LAYER M3 ;
      RECT 11.727 0.000 11.745 0.054 ;
    END
  END w0_wd_in[83]
  PIN w0_wd_in[84]
    DIRECTION OUTPUT ;
    USE SIGNAL ;
    SHAPE ABUTMENT ;
    PORT
      LAYER M3 ;
      RECT 12.015 0.000 12.033 0.054 ;
    END
  END w0_wd_in[84]
  PIN r0_rd_out[0]
    DIRECTION OUTPUT ;
    USE SIGNAL ;
    SHAPE ABUTMENT ;
    PORT
      LAYER M3 ;
      RECT 12.303 0.000 12.321 0.054 ;
    END
  END r0_rd_out[0]
  PIN r0_rd_out[1]
    DIRECTION OUTPUT ;
    USE SIGNAL ;
    SHAPE ABUTMENT ;
    PORT
      LAYER M3 ;
      RECT 12.591 0.000 12.609 0.054 ;
    END
  END r0_rd_out[1]
  PIN r0_rd_out[2]
    DIRECTION OUTPUT ;
    USE SIGNAL ;
    SHAPE ABUTMENT ;
    PORT
      LAYER M3 ;
      RECT 12.879 0.000 12.897 0.054 ;
    END
  END r0_rd_out[2]
  PIN r0_rd_out[3]
    DIRECTION OUTPUT ;
    USE SIGNAL ;
    SHAPE ABUTMENT ;
    PORT
      LAYER M3 ;
      RECT 13.167 0.000 13.185 0.054 ;
    END
  END r0_rd_out[3]
  PIN r0_rd_out[4]
    DIRECTION OUTPUT ;
    USE SIGNAL ;
    SHAPE ABUTMENT ;
    PORT
      LAYER M3 ;
      RECT 13.455 0.000 13.473 0.054 ;
    END
  END r0_rd_out[4]
  PIN r0_rd_out[5]
    DIRECTION OUTPUT ;
    USE SIGNAL ;
    SHAPE ABUTMENT ;
    PORT
      LAYER M3 ;
      RECT 13.743 0.000 13.761 0.054 ;
    END
  END r0_rd_out[5]
  PIN r0_rd_out[6]
    DIRECTION OUTPUT ;
    USE SIGNAL ;
    SHAPE ABUTMENT ;
    PORT
      LAYER M3 ;
      RECT 14.031 0.000 14.049 0.054 ;
    END
  END r0_rd_out[6]
  PIN r0_rd_out[7]
    DIRECTION OUTPUT ;
    USE SIGNAL ;
    SHAPE ABUTMENT ;
    PORT
      LAYER M3 ;
      RECT 14.319 0.000 14.337 0.054 ;
    END
  END r0_rd_out[7]
  PIN r0_rd_out[8]
    DIRECTION OUTPUT ;
    USE SIGNAL ;
    SHAPE ABUTMENT ;
    PORT
      LAYER M3 ;
      RECT 14.607 0.000 14.625 0.054 ;
    END
  END r0_rd_out[8]
  PIN r0_rd_out[9]
    DIRECTION OUTPUT ;
    USE SIGNAL ;
    SHAPE ABUTMENT ;
    PORT
      LAYER M3 ;
      RECT 14.895 0.000 14.913 0.054 ;
    END
  END r0_rd_out[9]
  PIN r0_rd_out[10]
    DIRECTION OUTPUT ;
    USE SIGNAL ;
    SHAPE ABUTMENT ;
    PORT
      LAYER M3 ;
      RECT 15.183 0.000 15.201 0.054 ;
    END
  END r0_rd_out[10]
  PIN r0_rd_out[11]
    DIRECTION OUTPUT ;
    USE SIGNAL ;
    SHAPE ABUTMENT ;
    PORT
      LAYER M3 ;
      RECT 15.471 0.000 15.489 0.054 ;
    END
  END r0_rd_out[11]
  PIN r0_rd_out[12]
    DIRECTION OUTPUT ;
    USE SIGNAL ;
    SHAPE ABUTMENT ;
    PORT
      LAYER M3 ;
      RECT 15.759 0.000 15.777 0.054 ;
    END
  END r0_rd_out[12]
  PIN r0_rd_out[13]
    DIRECTION OUTPUT ;
    USE SIGNAL ;
    SHAPE ABUTMENT ;
    PORT
      LAYER M3 ;
      RECT 16.047 0.000 16.065 0.054 ;
    END
  END r0_rd_out[13]
  PIN r0_rd_out[14]
    DIRECTION OUTPUT ;
    USE SIGNAL ;
    SHAPE ABUTMENT ;
    PORT
      LAYER M3 ;
      RECT 16.335 0.000 16.353 0.054 ;
    END
  END r0_rd_out[14]
  PIN r0_rd_out[15]
    DIRECTION OUTPUT ;
    USE SIGNAL ;
    SHAPE ABUTMENT ;
    PORT
      LAYER M3 ;
      RECT 16.623 0.000 16.641 0.054 ;
    END
  END r0_rd_out[15]
  PIN r0_rd_out[16]
    DIRECTION OUTPUT ;
    USE SIGNAL ;
    SHAPE ABUTMENT ;
    PORT
      LAYER M3 ;
      RECT 16.911 0.000 16.929 0.054 ;
    END
  END r0_rd_out[16]
  PIN r0_rd_out[17]
    DIRECTION OUTPUT ;
    USE SIGNAL ;
    SHAPE ABUTMENT ;
    PORT
      LAYER M3 ;
      RECT 17.199 0.000 17.217 0.054 ;
    END
  END r0_rd_out[17]
  PIN r0_rd_out[18]
    DIRECTION OUTPUT ;
    USE SIGNAL ;
    SHAPE ABUTMENT ;
    PORT
      LAYER M3 ;
      RECT 17.487 0.000 17.505 0.054 ;
    END
  END r0_rd_out[18]
  PIN r0_rd_out[19]
    DIRECTION OUTPUT ;
    USE SIGNAL ;
    SHAPE ABUTMENT ;
    PORT
      LAYER M3 ;
      RECT 17.775 0.000 17.793 0.054 ;
    END
  END r0_rd_out[19]
  PIN r0_rd_out[20]
    DIRECTION OUTPUT ;
    USE SIGNAL ;
    SHAPE ABUTMENT ;
    PORT
      LAYER M3 ;
      RECT 18.063 0.000 18.081 0.054 ;
    END
  END r0_rd_out[20]
  PIN r0_rd_out[21]
    DIRECTION OUTPUT ;
    USE SIGNAL ;
    SHAPE ABUTMENT ;
    PORT
      LAYER M3 ;
      RECT 18.351 0.000 18.369 0.054 ;
    END
  END r0_rd_out[21]
  PIN r0_rd_out[22]
    DIRECTION OUTPUT ;
    USE SIGNAL ;
    SHAPE ABUTMENT ;
    PORT
      LAYER M3 ;
      RECT 18.639 0.000 18.657 0.054 ;
    END
  END r0_rd_out[22]
  PIN r0_rd_out[23]
    DIRECTION OUTPUT ;
    USE SIGNAL ;
    SHAPE ABUTMENT ;
    PORT
      LAYER M3 ;
      RECT 18.927 0.000 18.945 0.054 ;
    END
  END r0_rd_out[23]
  PIN r0_rd_out[24]
    DIRECTION OUTPUT ;
    USE SIGNAL ;
    SHAPE ABUTMENT ;
    PORT
      LAYER M3 ;
      RECT 19.215 0.000 19.233 0.054 ;
    END
  END r0_rd_out[24]
  PIN r0_rd_out[25]
    DIRECTION OUTPUT ;
    USE SIGNAL ;
    SHAPE ABUTMENT ;
    PORT
      LAYER M3 ;
      RECT 19.503 0.000 19.521 0.054 ;
    END
  END r0_rd_out[25]
  PIN r0_rd_out[26]
    DIRECTION OUTPUT ;
    USE SIGNAL ;
    SHAPE ABUTMENT ;
    PORT
      LAYER M3 ;
      RECT 19.791 0.000 19.809 0.054 ;
    END
  END r0_rd_out[26]
  PIN r0_rd_out[27]
    DIRECTION OUTPUT ;
    USE SIGNAL ;
    SHAPE ABUTMENT ;
    PORT
      LAYER M3 ;
      RECT 20.079 0.000 20.097 0.054 ;
    END
  END r0_rd_out[27]
  PIN r0_rd_out[28]
    DIRECTION OUTPUT ;
    USE SIGNAL ;
    SHAPE ABUTMENT ;
    PORT
      LAYER M3 ;
      RECT 20.367 0.000 20.385 0.054 ;
    END
  END r0_rd_out[28]
  PIN r0_rd_out[29]
    DIRECTION OUTPUT ;
    USE SIGNAL ;
    SHAPE ABUTMENT ;
    PORT
      LAYER M3 ;
      RECT 20.655 0.000 20.673 0.054 ;
    END
  END r0_rd_out[29]
  PIN r0_rd_out[30]
    DIRECTION OUTPUT ;
    USE SIGNAL ;
    SHAPE ABUTMENT ;
    PORT
      LAYER M3 ;
      RECT 20.943 0.000 20.961 0.054 ;
    END
  END r0_rd_out[30]
  PIN r0_rd_out[31]
    DIRECTION OUTPUT ;
    USE SIGNAL ;
    SHAPE ABUTMENT ;
    PORT
      LAYER M3 ;
      RECT 21.231 0.000 21.249 0.054 ;
    END
  END r0_rd_out[31]
  PIN r0_rd_out[32]
    DIRECTION OUTPUT ;
    USE SIGNAL ;
    SHAPE ABUTMENT ;
    PORT
      LAYER M3 ;
      RECT 21.519 0.000 21.537 0.054 ;
    END
  END r0_rd_out[32]
  PIN r0_rd_out[33]
    DIRECTION OUTPUT ;
    USE SIGNAL ;
    SHAPE ABUTMENT ;
    PORT
      LAYER M3 ;
      RECT 21.807 0.000 21.825 0.054 ;
    END
  END r0_rd_out[33]
  PIN r0_rd_out[34]
    DIRECTION OUTPUT ;
    USE SIGNAL ;
    SHAPE ABUTMENT ;
    PORT
      LAYER M3 ;
      RECT 22.095 0.000 22.113 0.054 ;
    END
  END r0_rd_out[34]
  PIN r0_rd_out[35]
    DIRECTION OUTPUT ;
    USE SIGNAL ;
    SHAPE ABUTMENT ;
    PORT
      LAYER M3 ;
      RECT 22.383 0.000 22.401 0.054 ;
    END
  END r0_rd_out[35]
  PIN r0_rd_out[36]
    DIRECTION OUTPUT ;
    USE SIGNAL ;
    SHAPE ABUTMENT ;
    PORT
      LAYER M3 ;
      RECT 22.671 0.000 22.689 0.054 ;
    END
  END r0_rd_out[36]
  PIN r0_rd_out[37]
    DIRECTION OUTPUT ;
    USE SIGNAL ;
    SHAPE ABUTMENT ;
    PORT
      LAYER M3 ;
      RECT 22.959 0.000 22.977 0.054 ;
    END
  END r0_rd_out[37]
  PIN r0_rd_out[38]
    DIRECTION OUTPUT ;
    USE SIGNAL ;
    SHAPE ABUTMENT ;
    PORT
      LAYER M3 ;
      RECT 23.247 0.000 23.265 0.054 ;
    END
  END r0_rd_out[38]
  PIN r0_rd_out[39]
    DIRECTION OUTPUT ;
    USE SIGNAL ;
    SHAPE ABUTMENT ;
    PORT
      LAYER M3 ;
      RECT 23.535 0.000 23.553 0.054 ;
    END
  END r0_rd_out[39]
  PIN r0_rd_out[40]
    DIRECTION OUTPUT ;
    USE SIGNAL ;
    SHAPE ABUTMENT ;
    PORT
      LAYER M3 ;
      RECT 23.823 0.000 23.841 0.054 ;
    END
  END r0_rd_out[40]
  PIN r0_rd_out[41]
    DIRECTION OUTPUT ;
    USE SIGNAL ;
    SHAPE ABUTMENT ;
    PORT
      LAYER M3 ;
      RECT 24.111 0.000 24.129 0.054 ;
    END
  END r0_rd_out[41]
  PIN r0_rd_out[42]
    DIRECTION OUTPUT ;
    USE SIGNAL ;
    SHAPE ABUTMENT ;
    PORT
      LAYER M3 ;
      RECT 24.399 0.000 24.417 0.054 ;
    END
  END r0_rd_out[42]
  PIN r0_rd_out[43]
    DIRECTION OUTPUT ;
    USE SIGNAL ;
    SHAPE ABUTMENT ;
    PORT
      LAYER M3 ;
      RECT 12.303 10.308 12.321 10.362 ;
    END
  END r0_rd_out[43]
  PIN r0_rd_out[44]
    DIRECTION OUTPUT ;
    USE SIGNAL ;
    SHAPE ABUTMENT ;
    PORT
      LAYER M3 ;
      RECT 12.591 10.308 12.609 10.362 ;
    END
  END r0_rd_out[44]
  PIN r0_rd_out[45]
    DIRECTION OUTPUT ;
    USE SIGNAL ;
    SHAPE ABUTMENT ;
    PORT
      LAYER M3 ;
      RECT 12.879 10.308 12.897 10.362 ;
    END
  END r0_rd_out[45]
  PIN r0_rd_out[46]
    DIRECTION OUTPUT ;
    USE SIGNAL ;
    SHAPE ABUTMENT ;
    PORT
      LAYER M3 ;
      RECT 13.167 10.308 13.185 10.362 ;
    END
  END r0_rd_out[46]
  PIN r0_rd_out[47]
    DIRECTION OUTPUT ;
    USE SIGNAL ;
    SHAPE ABUTMENT ;
    PORT
      LAYER M3 ;
      RECT 13.455 10.308 13.473 10.362 ;
    END
  END r0_rd_out[47]
  PIN r0_rd_out[48]
    DIRECTION OUTPUT ;
    USE SIGNAL ;
    SHAPE ABUTMENT ;
    PORT
      LAYER M3 ;
      RECT 13.743 10.308 13.761 10.362 ;
    END
  END r0_rd_out[48]
  PIN r0_rd_out[49]
    DIRECTION OUTPUT ;
    USE SIGNAL ;
    SHAPE ABUTMENT ;
    PORT
      LAYER M3 ;
      RECT 14.031 10.308 14.049 10.362 ;
    END
  END r0_rd_out[49]
  PIN r0_rd_out[50]
    DIRECTION OUTPUT ;
    USE SIGNAL ;
    SHAPE ABUTMENT ;
    PORT
      LAYER M3 ;
      RECT 14.319 10.308 14.337 10.362 ;
    END
  END r0_rd_out[50]
  PIN r0_rd_out[51]
    DIRECTION OUTPUT ;
    USE SIGNAL ;
    SHAPE ABUTMENT ;
    PORT
      LAYER M3 ;
      RECT 14.607 10.308 14.625 10.362 ;
    END
  END r0_rd_out[51]
  PIN r0_rd_out[52]
    DIRECTION OUTPUT ;
    USE SIGNAL ;
    SHAPE ABUTMENT ;
    PORT
      LAYER M3 ;
      RECT 14.895 10.308 14.913 10.362 ;
    END
  END r0_rd_out[52]
  PIN r0_rd_out[53]
    DIRECTION OUTPUT ;
    USE SIGNAL ;
    SHAPE ABUTMENT ;
    PORT
      LAYER M3 ;
      RECT 15.183 10.308 15.201 10.362 ;
    END
  END r0_rd_out[53]
  PIN r0_rd_out[54]
    DIRECTION OUTPUT ;
    USE SIGNAL ;
    SHAPE ABUTMENT ;
    PORT
      LAYER M3 ;
      RECT 15.471 10.308 15.489 10.362 ;
    END
  END r0_rd_out[54]
  PIN r0_rd_out[55]
    DIRECTION OUTPUT ;
    USE SIGNAL ;
    SHAPE ABUTMENT ;
    PORT
      LAYER M3 ;
      RECT 15.759 10.308 15.777 10.362 ;
    END
  END r0_rd_out[55]
  PIN r0_rd_out[56]
    DIRECTION OUTPUT ;
    USE SIGNAL ;
    SHAPE ABUTMENT ;
    PORT
      LAYER M3 ;
      RECT 16.047 10.308 16.065 10.362 ;
    END
  END r0_rd_out[56]
  PIN r0_rd_out[57]
    DIRECTION OUTPUT ;
    USE SIGNAL ;
    SHAPE ABUTMENT ;
    PORT
      LAYER M3 ;
      RECT 16.335 10.308 16.353 10.362 ;
    END
  END r0_rd_out[57]
  PIN r0_rd_out[58]
    DIRECTION OUTPUT ;
    USE SIGNAL ;
    SHAPE ABUTMENT ;
    PORT
      LAYER M3 ;
      RECT 16.623 10.308 16.641 10.362 ;
    END
  END r0_rd_out[58]
  PIN r0_rd_out[59]
    DIRECTION OUTPUT ;
    USE SIGNAL ;
    SHAPE ABUTMENT ;
    PORT
      LAYER M3 ;
      RECT 16.911 10.308 16.929 10.362 ;
    END
  END r0_rd_out[59]
  PIN r0_rd_out[60]
    DIRECTION OUTPUT ;
    USE SIGNAL ;
    SHAPE ABUTMENT ;
    PORT
      LAYER M3 ;
      RECT 17.199 10.308 17.217 10.362 ;
    END
  END r0_rd_out[60]
  PIN r0_rd_out[61]
    DIRECTION OUTPUT ;
    USE SIGNAL ;
    SHAPE ABUTMENT ;
    PORT
      LAYER M3 ;
      RECT 17.487 10.308 17.505 10.362 ;
    END
  END r0_rd_out[61]
  PIN r0_rd_out[62]
    DIRECTION OUTPUT ;
    USE SIGNAL ;
    SHAPE ABUTMENT ;
    PORT
      LAYER M3 ;
      RECT 17.775 10.308 17.793 10.362 ;
    END
  END r0_rd_out[62]
  PIN r0_rd_out[63]
    DIRECTION OUTPUT ;
    USE SIGNAL ;
    SHAPE ABUTMENT ;
    PORT
      LAYER M3 ;
      RECT 18.063 10.308 18.081 10.362 ;
    END
  END r0_rd_out[63]
  PIN r0_rd_out[64]
    DIRECTION OUTPUT ;
    USE SIGNAL ;
    SHAPE ABUTMENT ;
    PORT
      LAYER M3 ;
      RECT 18.351 10.308 18.369 10.362 ;
    END
  END r0_rd_out[64]
  PIN r0_rd_out[65]
    DIRECTION OUTPUT ;
    USE SIGNAL ;
    SHAPE ABUTMENT ;
    PORT
      LAYER M3 ;
      RECT 18.639 10.308 18.657 10.362 ;
    END
  END r0_rd_out[65]
  PIN r0_rd_out[66]
    DIRECTION OUTPUT ;
    USE SIGNAL ;
    SHAPE ABUTMENT ;
    PORT
      LAYER M3 ;
      RECT 18.927 10.308 18.945 10.362 ;
    END
  END r0_rd_out[66]
  PIN r0_rd_out[67]
    DIRECTION OUTPUT ;
    USE SIGNAL ;
    SHAPE ABUTMENT ;
    PORT
      LAYER M3 ;
      RECT 19.215 10.308 19.233 10.362 ;
    END
  END r0_rd_out[67]
  PIN r0_rd_out[68]
    DIRECTION OUTPUT ;
    USE SIGNAL ;
    SHAPE ABUTMENT ;
    PORT
      LAYER M3 ;
      RECT 19.503 10.308 19.521 10.362 ;
    END
  END r0_rd_out[68]
  PIN r0_rd_out[69]
    DIRECTION OUTPUT ;
    USE SIGNAL ;
    SHAPE ABUTMENT ;
    PORT
      LAYER M3 ;
      RECT 19.791 10.308 19.809 10.362 ;
    END
  END r0_rd_out[69]
  PIN r0_rd_out[70]
    DIRECTION OUTPUT ;
    USE SIGNAL ;
    SHAPE ABUTMENT ;
    PORT
      LAYER M3 ;
      RECT 20.079 10.308 20.097 10.362 ;
    END
  END r0_rd_out[70]
  PIN r0_rd_out[71]
    DIRECTION OUTPUT ;
    USE SIGNAL ;
    SHAPE ABUTMENT ;
    PORT
      LAYER M3 ;
      RECT 20.367 10.308 20.385 10.362 ;
    END
  END r0_rd_out[71]
  PIN r0_rd_out[72]
    DIRECTION OUTPUT ;
    USE SIGNAL ;
    SHAPE ABUTMENT ;
    PORT
      LAYER M3 ;
      RECT 20.655 10.308 20.673 10.362 ;
    END
  END r0_rd_out[72]
  PIN r0_rd_out[73]
    DIRECTION OUTPUT ;
    USE SIGNAL ;
    SHAPE ABUTMENT ;
    PORT
      LAYER M3 ;
      RECT 20.943 10.308 20.961 10.362 ;
    END
  END r0_rd_out[73]
  PIN r0_rd_out[74]
    DIRECTION OUTPUT ;
    USE SIGNAL ;
    SHAPE ABUTMENT ;
    PORT
      LAYER M3 ;
      RECT 21.231 10.308 21.249 10.362 ;
    END
  END r0_rd_out[74]
  PIN r0_rd_out[75]
    DIRECTION OUTPUT ;
    USE SIGNAL ;
    SHAPE ABUTMENT ;
    PORT
      LAYER M3 ;
      RECT 21.519 10.308 21.537 10.362 ;
    END
  END r0_rd_out[75]
  PIN r0_rd_out[76]
    DIRECTION OUTPUT ;
    USE SIGNAL ;
    SHAPE ABUTMENT ;
    PORT
      LAYER M3 ;
      RECT 21.807 10.308 21.825 10.362 ;
    END
  END r0_rd_out[76]
  PIN r0_rd_out[77]
    DIRECTION OUTPUT ;
    USE SIGNAL ;
    SHAPE ABUTMENT ;
    PORT
      LAYER M3 ;
      RECT 22.095 10.308 22.113 10.362 ;
    END
  END r0_rd_out[77]
  PIN r0_rd_out[78]
    DIRECTION OUTPUT ;
    USE SIGNAL ;
    SHAPE ABUTMENT ;
    PORT
      LAYER M3 ;
      RECT 22.383 10.308 22.401 10.362 ;
    END
  END r0_rd_out[78]
  PIN r0_rd_out[79]
    DIRECTION OUTPUT ;
    USE SIGNAL ;
    SHAPE ABUTMENT ;
    PORT
      LAYER M3 ;
      RECT 22.671 10.308 22.689 10.362 ;
    END
  END r0_rd_out[79]
  PIN r0_rd_out[80]
    DIRECTION OUTPUT ;
    USE SIGNAL ;
    SHAPE ABUTMENT ;
    PORT
      LAYER M3 ;
      RECT 22.959 10.308 22.977 10.362 ;
    END
  END r0_rd_out[80]
  PIN r0_rd_out[81]
    DIRECTION OUTPUT ;
    USE SIGNAL ;
    SHAPE ABUTMENT ;
    PORT
      LAYER M3 ;
      RECT 23.247 10.308 23.265 10.362 ;
    END
  END r0_rd_out[81]
  PIN r0_rd_out[82]
    DIRECTION OUTPUT ;
    USE SIGNAL ;
    SHAPE ABUTMENT ;
    PORT
      LAYER M3 ;
      RECT 23.535 10.308 23.553 10.362 ;
    END
  END r0_rd_out[82]
  PIN r0_rd_out[83]
    DIRECTION OUTPUT ;
    USE SIGNAL ;
    SHAPE ABUTMENT ;
    PORT
      LAYER M3 ;
      RECT 23.823 10.308 23.841 10.362 ;
    END
  END r0_rd_out[83]
  PIN r0_rd_out[84]
    DIRECTION OUTPUT ;
    USE SIGNAL ;
    SHAPE ABUTMENT ;
    PORT
      LAYER M3 ;
      RECT 24.111 10.308 24.129 10.362 ;
    END
  END r0_rd_out[84]
  PIN w0_addr_in[0]
    DIRECTION INPUT ;
    USE SIGNAL ;
    SHAPE ABUTMENT ;
    PORT
      LAYER M4 ;
      RECT 0.000 8.724 0.072 8.748 ;
    END
  END w0_addr_in[0]
  PIN w0_addr_in[1]
    DIRECTION INPUT ;
    USE SIGNAL ;
    SHAPE ABUTMENT ;
    PORT
      LAYER M4 ;
      RECT 0.000 8.916 0.072 8.940 ;
    END
  END w0_addr_in[1]
  PIN w0_addr_in[2]
    DIRECTION INPUT ;
    USE SIGNAL ;
    SHAPE ABUTMENT ;
    PORT
      LAYER M4 ;
      RECT 27.028 8.340 27.100 8.364 ;
    END
  END w0_addr_in[2]
  PIN w0_addr_in[3]
    DIRECTION INPUT ;
    USE SIGNAL ;
    SHAPE ABUTMENT ;
    PORT
      LAYER M4 ;
      RECT 27.028 8.532 27.100 8.556 ;
    END
  END w0_addr_in[3]
  PIN r0_addr_in[0]
    DIRECTION INPUT ;
    USE SIGNAL ;
    SHAPE ABUTMENT ;
    PORT
      LAYER M4 ;
      RECT 0.000 9.108 0.072 9.132 ;
    END
  END r0_addr_in[0]
  PIN r0_addr_in[1]
    DIRECTION INPUT ;
    USE SIGNAL ;
    SHAPE ABUTMENT ;
    PORT
      LAYER M4 ;
      RECT 0.000 9.300 0.072 9.324 ;
    END
  END r0_addr_in[1]
  PIN r0_addr_in[2]
    DIRECTION INPUT ;
    USE SIGNAL ;
    SHAPE ABUTMENT ;
    PORT
      LAYER M4 ;
      RECT 27.028 8.724 27.100 8.748 ;
    END
  END r0_addr_in[2]
  PIN r0_addr_in[3]
    DIRECTION INPUT ;
    USE SIGNAL ;
    SHAPE ABUTMENT ;
    PORT
      LAYER M4 ;
      RECT 27.028 8.916 27.100 8.940 ;
    END
  END r0_addr_in[3]
  PIN w0_we_in
    DIRECTION INPUT ;
    USE SIGNAL ;
    SHAPE ABUTMENT ;
    PORT
      LAYER M3 ;
      RECT 24.399 10.308 24.417 10.362 ;
    END
  END w0_we_in
  PIN w0_ce_in
    DIRECTION INPUT ;
    USE SIGNAL ;
    SHAPE ABUTMENT ;
    PORT
      LAYER M3 ;
      RECT 24.687 10.308 24.705 10.362 ;
    END
  END w0_ce_in
  PIN w0_clk
    DIRECTION INPUT ;
    USE SIGNAL ;
    SHAPE ABUTMENT ;
    PORT
      LAYER M3 ;
      RECT 24.975 10.308 24.993 10.362 ;
    END
  END w0_clk
  PIN r0_ce_in
    DIRECTION INPUT ;
    USE SIGNAL ;
    SHAPE ABUTMENT ;
    PORT
      LAYER M3 ;
      RECT 25.263 10.308 25.281 10.362 ;
    END
  END r0_ce_in
  PIN r0_clk
    DIRECTION INPUT ;
    USE SIGNAL ;
    SHAPE ABUTMENT ;
    PORT
      LAYER M3 ;
      RECT 25.551 10.308 25.569 10.362 ;
    END
  END r0_clk
  PIN VSS
    DIRECTION INOUT ;
    USE GROUND ;
    PORT
      LAYER M4 ;
      RECT 0.216 0.240 26.884 0.336 ;
      RECT 0.216 1.008 26.884 1.104 ;
      RECT 0.216 1.776 26.884 1.872 ;
      RECT 0.216 2.544 26.884 2.640 ;
      RECT 0.216 3.312 26.884 3.408 ;
      RECT 0.216 4.080 26.884 4.176 ;
      RECT 0.216 4.848 26.884 4.944 ;
      RECT 0.216 5.616 26.884 5.712 ;
      RECT 0.216 6.384 26.884 6.480 ;
      RECT 0.216 7.152 26.884 7.248 ;
      RECT 0.216 7.920 26.884 8.016 ;
      RECT 0.216 8.688 26.884 8.784 ;
      RECT 0.216 9.456 26.884 9.552 ;
      RECT 0.216 10.224 26.884 10.320 ;
    END
  END VSS
  PIN VDD
    DIRECTION INOUT ;
    USE POWER ;
    PORT
      LAYER M4 ;
      RECT 0.216 0.240 26.884 0.336 ;
      RECT 0.216 1.008 26.884 1.104 ;
      RECT 0.216 1.776 26.884 1.872 ;
      RECT 0.216 2.544 26.884 2.640 ;
      RECT 0.216 3.312 26.884 3.408 ;
      RECT 0.216 4.080 26.884 4.176 ;
      RECT 0.216 4.848 26.884 4.944 ;
      RECT 0.216 5.616 26.884 5.712 ;
      RECT 0.216 6.384 26.884 6.480 ;
      RECT 0.216 7.152 26.884 7.248 ;
      RECT 0.216 7.920 26.884 8.016 ;
      RECT 0.216 8.688 26.884 8.784 ;
      RECT 0.216 9.456 26.884 9.552 ;
      RECT 0.216 10.224 26.884 10.320 ;
    END
  END VDD
  OBS
    LAYER M1 ;
    RECT 0 0 27.100 10.362 ;
    LAYER M2 ;
    RECT 0 0 27.100 10.362 ;
    LAYER M3 ;
    RECT 0 0 27.100 10.362 ;
    LAYER M4 ;
    RECT 0 0 27.100 10.362 ;
  END
END fakeram_85x16_1r1w

END LIBRARY
